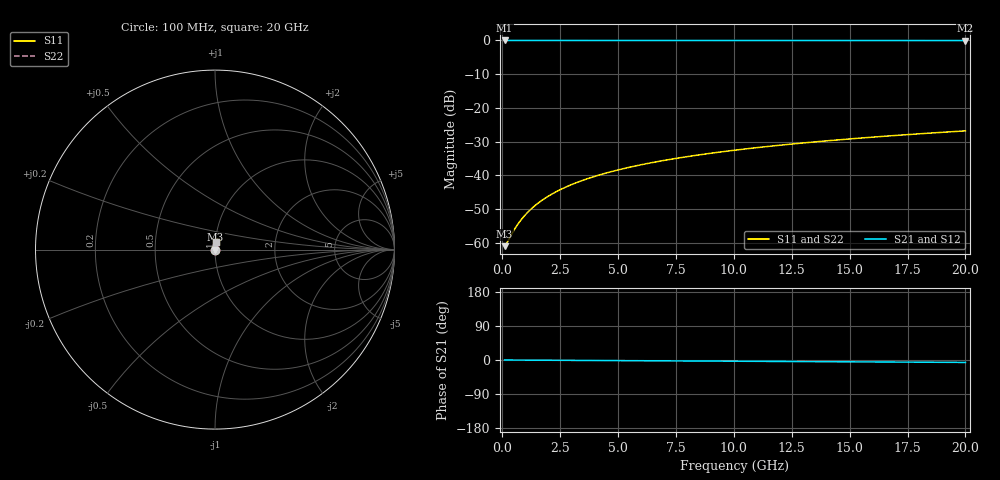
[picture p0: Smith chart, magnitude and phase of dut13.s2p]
! Touchstone file exported from HFSS 2026.1.0
!  File:  C:/ffzhzh/LocalFiles/Ansys_Project_Files/temp_test_TSV_13_1782978255_45748.aedt
!  Generated:  03:46:25 PM Jul  2, 2026
!  Design:  TSV
!  Project:  temp_test_TSV_13_1782978255_45748
! Variables:
!  h_bsmrdl = 2um
!  h_ox = 20um
!  h_rdl = 5um
!  h_sub = 59.59um
!  h_tmrdl = 5um
!  h_tsv = 59.59um
!  h_via = 3um
!  l_bsmrdl = 300um
!  l_sub = 405.76um
!  l_tmrdl = 200um
!  m_sub = 200um
!  pitch = 22.24um
!  r_tsv = 2.88um
!  s_tmrdl = 10um
!  w_bsmrdl = 18um
!  w_sub = 500um
!  w_tmrdl = 12um
!  x_tsv_center1 = 206um
!  x_tsv_center2 = 524um
!  x_tsv_center3 = 736um
!  x_tsv_center4 = 1054um
!  x_tsv_center5 = 1266um
!  x_tsv_center6 = 1584um
# GHz S MA R 50.000000
! Terminal data exported
! Port[1] = TSV1_1_T1
! Port[2] = TSV1_1_T2
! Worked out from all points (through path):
!   200 points, 100 MHz to 20 GHz, reference 50 ohm
!   highest |S21| = -0.01 dB at 100 MHz (marker M1); lowest = 0.0 dB at 20 GHz (marker M2)
!   lowest |S11| = -61.0 dB at 100 MHz (marker M3), VSWR 1.00, Z = 50.1 + j0.0256 ohm
!   |S11| at or under -10 dB: start of sweep to end of sweep
!   |S22| runs from -61.0 to -26.8 dB; largest |S21 - S12| = 2.7e-15
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0.1  0.0008917 16.6  0.9991 -0.0  0.9991 -0.0  0.0008917 16.6
! Gamma 0 0 0 0
! Port Impedance 50 0 50 0
0.2  0.001001 30.5  0.9991 -0.1  0.9991 -0.1  0.001001 30.5
0.5  0.00153 54.2  0.9991 -0.2  0.9991 -0.2  0.00153 54.2
0.6  0.001736 58.6  0.9991 -0.2  0.9991 -0.2  0.001736 58.6
0.8  0.002167 64.9  0.9991 -0.3  0.9991 -0.3  0.002167 64.9
0.9  0.002389 67.1  0.9991 -0.3  0.9991 -0.3  0.002389 67.1
1.1  0.002841 70.6  0.9991 -0.4  0.9991 -0.4  0.002841 70.6
1.4  0.003534 74.1  0.9991 -0.5  0.9991 -0.5  0.003534 74.1
1.8  0.004472 77.0  0.999 -0.6  0.999 -0.6  0.004472 77.0
2.3  0.005654 79.1  0.999 -0.8  0.999 -0.8  0.005654 79.1
2.9  0.007078 80.6  0.9989 -0.9  0.9989 -0.9  0.007078 80.6
3.5  0.0085 81.5  0.9989 -1.1  0.9989 -1.1  0.0085 81.5
4.2  0.01016 82.1  0.9988 -1.4  0.9988 -1.4  0.01016 82.1
5  0.01204 82.4  0.9987 -1.6  0.9987 -1.6  0.01204 82.4
5.9  0.01414 82.6  0.9986 -1.9  0.9986 -1.9  0.01414 82.6
6.8  0.01622 82.6  0.9984 -2.2  0.9984 -2.2  0.01622 82.6
8.3  0.01966 82.5  0.9982 -2.7  0.9982 -2.7  0.01966 82.5
10.1  0.02375 82.3  0.9979 -3.3  0.9979 -3.3  0.02375 82.3
11.7  0.02734 82.0  0.9976 -3.8  0.9976 -3.8  0.02734 82.0
13.4  0.03113 81.6  0.9973 -4.3  0.9973 -4.3  0.03113 81.6
16.7  0.03842 80.9  0.9968 -5.4  0.9968 -5.4  0.03842 80.9
20  0.04567 80.2  0.9962 -6.4  0.9962 -6.4  0.04567 80.2
